One B-rep face of a CAD part: STEP entity #206.
In plain terms, the planar face has unit normal (1, 0, 0).
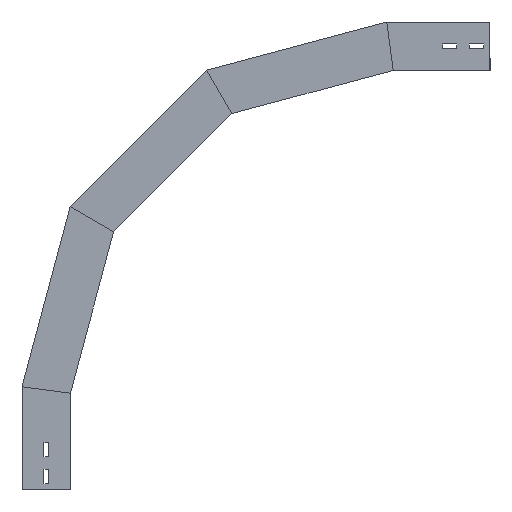
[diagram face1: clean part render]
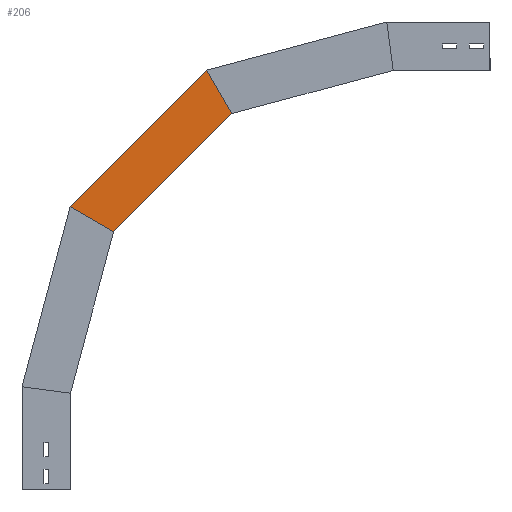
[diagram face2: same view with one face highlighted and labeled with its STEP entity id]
Its self-contained STEP definition (entity closure, numbers rounded to 3 decimals):
#65 = DIRECTION ( 'NONE',  ( 0., -0.707, 0.707 ) ) ;
#68 = DIRECTION ( 'NONE',  ( 0., 0., -1. ) ) ;
#79 = PLANE ( 'NONE',  #1677 ) ;
#120 = DIRECTION ( 'NONE',  ( 0., -0.866, -0.5 ) ) ;
#203 = CARTESIAN_POINT ( 'NONE',  ( 0., -51.332, 384.473 ) ) ;
#206 = ADVANCED_FACE ( 'NONE', ( #540 ), #79, .T. ) ;
#231 = CARTESIAN_POINT ( 'NONE',  ( 0., -51.332, 384.473 ) ) ;
#245 = VECTOR ( 'NONE', #1009, 1000. ) ;
#256 = CARTESIAN_POINT ( 'NONE',  ( 0., -67.034, 400.175 ) ) ;
#264 = LINE ( 'NONE', #1125, #992 ) ;
#371 = VERTEX_POINT ( 'NONE', #1029 ) ;
#391 = VERTEX_POINT ( 'NONE', #1570 ) ;
#440 = CARTESIAN_POINT ( 'NONE',  ( 0., -250.175, 583.315 ) ) ;
#452 = CARTESIAN_POINT ( 'NONE',  ( 0., -286.565, 520.285 ) ) ;
#532 = LINE ( 'NONE', #1157, #994 ) ;
#540 = FACE_OUTER_BOUND ( 'NONE', #1557, .T. ) ;
#588 = VECTOR ( 'NONE', #65, 1000. ) ;
#652 = DIRECTION ( 'NONE',  ( 1., 0., 0. ) ) ;
#656 = ORIENTED_EDGE ( 'NONE', *, *, #850, .T. ) ;
#701 = DIRECTION ( 'NONE',  ( 0., -0.707, 0.707 ) ) ;
#743 = EDGE_CURVE ( 'NONE', #805, #915, #1693, .T. ) ;
#805 = VERTEX_POINT ( 'NONE', #256 ) ;
#850 = EDGE_CURVE ( 'NONE', #371, #391, #264, .T. ) ;
#915 = VERTEX_POINT ( 'NONE', #440 ) ;
#985 = ORIENTED_EDGE ( 'NONE', *, *, #1521, .F. ) ;
#992 = VECTOR ( 'NONE', #701, 1000. ) ;
#994 = VECTOR ( 'NONE', #120, 1000. ) ;
#1009 = DIRECTION ( 'NONE',  ( 0., -0.5, -0.866 ) ) ;
#1025 = ORIENTED_EDGE ( 'NONE', *, *, #743, .F. ) ;
#1029 = CARTESIAN_POINT ( 'NONE',  ( 0., 0.209, 438.998 ) ) ;
#1125 = CARTESIAN_POINT ( 'NONE',  ( 0., 1.701, 437.506 ) ) ;
#1157 = CARTESIAN_POINT ( 'NONE',  ( 0., -127.544, 365.239 ) ) ;
#1181 = LINE ( 'NONE', #452, #245 ) ;
#1263 = EDGE_CURVE ( 'NONE', #391, #915, #1181, .T. ) ;
#1303 = ORIENTED_EDGE ( 'NONE', *, *, #1263, .T. ) ;
#1521 = EDGE_CURVE ( 'NONE', #371, #805, #532, .T. ) ;
#1557 = EDGE_LOOP ( 'NONE', ( #656, #1303, #1025, #985 ) ) ;
#1570 = CARTESIAN_POINT ( 'NONE',  ( 0., -211.352, 650.559 ) ) ;
#1677 = AXIS2_PLACEMENT_3D ( 'NONE', #231, #652, #68 ) ;
#1693 = LINE ( 'NONE', #203, #588 ) ;
